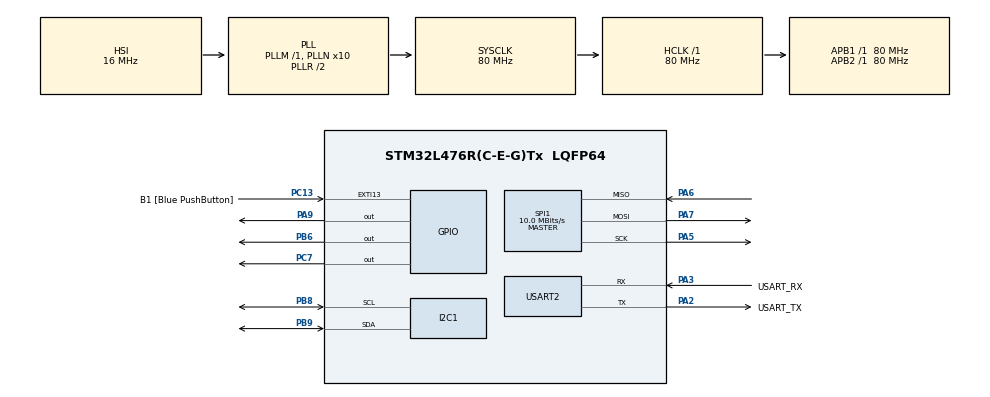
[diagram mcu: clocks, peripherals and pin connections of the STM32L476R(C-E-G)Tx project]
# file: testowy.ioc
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I2C1.Timing=0x10909CEC
Mcu.Family=STM32L4
Mcu.Name=STM32L476R(C-E-G)Tx
Mcu.Package=LQFP64
NVIC.PriorityGroup=NVIC_PRIORITYGROUP_4
PA13\ (JTMS-SWDIO).GPIO_Label=TMS
PA13\ (JTMS-SWDIO).Mode=Serial_Wire
PA13\ (JTMS-SWDIO).Signal=SYS_JTMS-SWDIO
PA14\ (JTCK-SWCLK).GPIO_Label=TCK
PA14\ (JTCK-SWCLK).Mode=Serial_Wire
PA14\ (JTCK-SWCLK).Signal=SYS_JTCK-SWCLK
PA2.GPIO_Label=USART_TX
PA2.GPIO_Mode=GPIO_MODE_AF_PP
PA2.GPIO_PuPd=GPIO_NOPULL
PA2.GPIO_Speed=GPIO_SPEED_FREQ_VERY_HIGH
PA2.Mode=Asynchronous
PA2.Signal=USART2_TX
PA3.GPIO_Label=USART_RX
PA3.GPIO_Mode=GPIO_MODE_AF_PP
PA3.GPIO_PuPd=GPIO_NOPULL
PA3.GPIO_Speed=GPIO_SPEED_FREQ_VERY_HIGH
PA3.Mode=Asynchronous
PA3.Signal=USART2_RX
PA5.Mode=Full_Duplex_Master
PA5.Signal=SPI1_SCK
PA6.Mode=Full_Duplex_Master
PA6.Signal=SPI1_MISO
PA7.Mode=Full_Duplex_Master
PA7.Signal=SPI1_MOSI
PA9.Signal=GPIO_Output
PB3\ (JTDO-TRACESWO).GPIO_Label=SWO
PB3\ (JTDO-TRACESWO).Signal=SYS_JTDO-SWO
PB6.Signal=GPIO_Output
PB8.Mode=I2C
PB8.Signal=I2C1_SCL
PB9.Mode=I2C
PB9.Signal=I2C1_SDA
PC13.GPIO_Label=B1 [Blue PushButton]
PC13.GPIO_ModeDefaultEXTI=GPIO_MODE_IT_FALLING
PC13.GPIO_PuPd=GPIO_NOPULL
PC13.Signal=GPXTI13
PC14-OSC32_IN\ (PC14).Mode=LSE-External-Oscillator
PC14-OSC32_IN\ (PC14).Signal=RCC_OSC32_IN
PC15-OSC32_OUT\ (PC15).Mode=LSE-External-Oscillator
PC15-OSC32_OUT\ (PC15).Signal=RCC_OSC32_OUT
PC7.Signal=GPIO_Output
PH0-OSC_IN\ (PH0).Signal=RCC_OSC_IN
PH1-OSC_OUT\ (PH1).Signal=RCC_OSC_OUT
ProjectManager.HeapSize=0x200
ProjectManager.StackSize=0x400
ProjectManager.TargetToolchain=STM32CubeIDE
RCC.ADCFreq_Value=64000000
RCC.AHBFreq_Value=80000000
RCC.APB1Freq_Value=80000000
RCC.APB1TimFreq_Value=80000000
RCC.APB2Freq_Value=80000000
RCC.APB2TimFreq_Value=80000000
RCC.CortexFreq_Value=80000000
RCC.HCLKFreq_Value=80000000
RCC.HSE_VALUE=8000000
RCC.HSI_VALUE=16000000
RCC.MSI_VALUE=4000000
RCC.PLLN=10
RCC.PLLSourceVirtual=RCC_PLLSOURCE_HSI
RCC.PREFETCH_ENABLE=1
RCC.SYSCLKFreq_VALUE=80000000
RCC.SYSCLKSource=RCC_SYSCLKSOURCE_PLLCLK
RCC.USBFreq_Value=64000000
RCC.VCOOutputFreq_Value=160000000
SPI1.BaudRatePrescaler=SPI_BAUDRATEPRESCALER_8
SPI1.CalculateBaudRate=10.0 MBits/s
SPI1.DataSize=SPI_DATASIZE_8BIT
SPI1.Direction=SPI_DIRECTION_2LINES
SPI1.Mode=SPI_MODE_MASTER
SPI1.VirtualType=VM_MASTER
USART2.VirtualMode-Asynchronous=VM_ASYNC
board=NUCLEO-L476RG

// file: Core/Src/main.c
/* USER CODE BEGIN Header */
/**
  ******************************************************************************
  * @file           : main.c
  * @brief          : Main program body
  ******************************************************************************
  * @attention
  *
  * Copyright (c) 2024 STMicroelectronics.
  * All rights reserved.
  *
  * This software is licensed under terms that can be found in the LICENSE file
  * in the root directory of this software component.
  * If no LICENSE file comes with this software, it is provided AS-IS.
  *
  ******************************************************************************
  */
/* USER CODE END Header */
#include "main.h"

#include "ssd1306.h"
#include "ssd1306_tests.h"
#include "sx1509.h"

#include <stdbool.h>

I2C_HandleTypeDef hi2c1;

SPI_HandleTypeDef hspi1;

UART_HandleTypeDef huart2;

void SystemClock_Config(void);
void loop(void);
static void MX_GPIO_Init(void);
static void MX_USART2_UART_Init(void);
static void MX_I2C1_Init(void);
static void MX_SPI1_Init(void);

/* USER CODE BEGIN 0 */

static uint16_t readWordINA(uint8_t reg)
{
	HAL_StatusTypeDef ret;
	uint8_t buf[2] = {reg};
	ret = HAL_I2C_Master_Transmit(&SX1509_I2C_PORT, INAAddress, buf, 1, i2CTimeout);
	if ( ret == HAL_OK )
	{
		ret = HAL_I2C_Master_Receive(&SX1509_I2C_PORT, INAAddress, buf, 2, i2CTimeout);
		if ( ret == HAL_OK )
		{
			uint16_t tmp = buf[0];
			tmp <<= 8;
			tmp |= buf[1];
			return tmp;
		}
	}
	return 0xFFFF;
}

/* USER CODE END 0 */

void loop() {
	// Blue button pressed - repeast the test
    if(HAL_GPIO_ReadPin(GPIOC, GPIO_PIN_13) == GPIO_PIN_RESET) {

		ssd1306_TestAll();

    }

	HAL_Delay(150);
}

int main(void)
{

  /* USER CODE BEGIN 1 */
uint16_t reg=0;
  /* USER CODE END 1 */

  /* MCU Configuration--------------------------------------------------------*/

  /* Reset of all peripherals, Initializes the Flash interface and the Systick. */
  HAL_Init();

  /* Configure the system clock */
  SystemClock_Config();

  /* Initialize all configured peripherals */
  MX_GPIO_Init();
  MX_USART2_UART_Init();
  MX_I2C1_Init();
  MX_SPI1_Init();
  /* USER CODE BEGIN 2 */

	reg = readWord(0x13);

 	reg = readWordINA(0x3F);

  /* USER CODE END 2 */

  /* Infinite loop */
  while (1)
  {

	  loop();
    /* USER CODE BEGIN 3 */

	  reg = readWordINA(0x07);
  }
  /* USER CODE END 3 */
}

void SystemClock_Config(void)
{
  RCC_OscInitTypeDef RCC_OscInitStruct = {0};
  RCC_ClkInitTypeDef RCC_ClkInitStruct = {0};

  /** Configure the main internal regulator output voltage
  */
  if (HAL_PWREx_ControlVoltageScaling(PWR_REGULATOR_VOLTAGE_SCALE1) != HAL_OK)
  {
    Error_Handler();
  }

  /** Initializes the RCC Oscillators according to the specified parameters
  * in the RCC_OscInitTypeDef structure.
  */
  RCC_OscInitStruct.OscillatorType = RCC_OSCILLATORTYPE_HSI;
  RCC_OscInitStruct.HSIState = RCC_HSI_ON;
  RCC_OscInitStruct.HSICalibrationValue = RCC_HSICALIBRATION_DEFAULT;
  RCC_OscInitStruct.PLL.PLLState = RCC_PLL_ON;
  RCC_OscInitStruct.PLL.PLLSource = RCC_PLLSOURCE_HSI;
  RCC_OscInitStruct.PLL.PLLM = 1;
  RCC_OscInitStruct.PLL.PLLN = 10;
  RCC_OscInitStruct.PLL.PLLP = RCC_PLLP_DIV7;
  RCC_OscInitStruct.PLL.PLLQ = RCC_PLLQ_DIV2;
  RCC_OscInitStruct.PLL.PLLR = RCC_PLLR_DIV2;
  if (HAL_RCC_OscConfig(&RCC_OscInitStruct) != HAL_OK)
  {
    Error_Handler();
  }

  /** Initializes the CPU, AHB and APB buses clocks
  */
  RCC_ClkInitStruct.ClockType = RCC_CLOCKTYPE_HCLK|RCC_CLOCKTYPE_SYSCLK
                              |RCC_CLOCKTYPE_PCLK1|RCC_CLOCKTYPE_PCLK2;
  RCC_ClkInitStruct.SYSCLKSource = RCC_SYSCLKSOURCE_PLLCLK;
  RCC_ClkInitStruct.AHBCLKDivider = RCC_SYSCLK_DIV1;
  RCC_ClkInitStruct.APB1CLKDivider = RCC_HCLK_DIV1;
  RCC_ClkInitStruct.APB2CLKDivider = RCC_HCLK_DIV1;

  if (HAL_RCC_ClockConfig(&RCC_ClkInitStruct, FLASH_LATENCY_4) != HAL_OK)
  {
    Error_Handler();
  }
}

static void MX_I2C1_Init(void)
{

  /* USER CODE BEGIN I2C1_Init 0 */
		  GPIO_InitTypeDef GPIO_InitStruct;
		  RCC_PeriphCLKInitTypeDef PeriphClkInit = {0};
		  /** Initializes the peripherals clock  */
		  PeriphClkInit.PeriphClockSelection = RCC_PERIPHCLK_I2C1;
		  PeriphClkInit.Usart2ClockSelection = RCC_I2C1CLKSOURCE_PCLK1;
		  HAL_RCCEx_PeriphCLKConfig(&PeriphClkInit);

		  /* Enable Peripheral clock */
		  __HAL_RCC_I2C1_CLK_ENABLE();

		    __HAL_RCC_GPIOB_CLK_ENABLE();
		    /**USART2 GPIO Configuration
		    PA2     ------> USART2_TX
		    PA3     ------> USART2_RX
		    */
		    GPIO_InitStruct.Pin = GPIO_PIN_8 | GPIO_PIN_9;
		    GPIO_InitStruct.Mode = GPIO_MODE_AF_PP;
		    GPIO_InitStruct.Pull = GPIO_PULLUP;
		    GPIO_InitStruct.Speed = GPIO_SPEED_FREQ_VERY_HIGH;
		    GPIO_InitStruct.Alternate = GPIO_AF4_I2C1;
		    HAL_GPIO_Init(GPIOB, &GPIO_InitStruct);

  /* USER CODE END I2C1_Init 0 */

  hi2c1.Instance = I2C1;
  hi2c1.Init.Timing = 0x10909CEC;
  hi2c1.Init.OwnAddress1 = 0;
  hi2c1.Init.AddressingMode = I2C_ADDRESSINGMODE_7BIT;
  hi2c1.Init.DualAddressMode = I2C_DUALADDRESS_DISABLE;
  hi2c1.Init.OwnAddress2 = 0;
  hi2c1.Init.OwnAddress2Masks = I2C_OA2_NOMASK;
  hi2c1.Init.GeneralCallMode = I2C_GENERALCALL_DISABLE;
  hi2c1.Init.NoStretchMode = I2C_NOSTRETCH_DISABLE;
  if (HAL_I2C_Init(&hi2c1) != HAL_OK)
  {
    Error_Handler();
  }

  /** Configure Analogue filter
  */
  if (HAL_I2CEx_ConfigAnalogFilter(&hi2c1, I2C_ANALOGFILTER_ENABLE) != HAL_OK)
  {
    Error_Handler();
  }

  /** Configure Digital filter
  */
  if (HAL_I2CEx_ConfigDigitalFilter(&hi2c1, 0) != HAL_OK)
  {
    Error_Handler();
  }

}

static void MX_SPI1_Init(void)
{

  /* SPI1 parameter configuration*/
  hspi1.Instance = SPI1;
  hspi1.Init.Mode = SPI_MODE_MASTER;
  hspi1.Init.Direction = SPI_DIRECTION_2LINES;
  hspi1.Init.DataSize = SPI_DATASIZE_8BIT;
  hspi1.Init.CLKPolarity = SPI_POLARITY_LOW;
  hspi1.Init.CLKPhase = SPI_PHASE_1EDGE;
  hspi1.Init.NSS = SPI_NSS_SOFT;
  hspi1.Init.BaudRatePrescaler = SPI_BAUDRATEPRESCALER_8;
  hspi1.Init.FirstBit = SPI_FIRSTBIT_MSB;
  hspi1.Init.TIMode = SPI_TIMODE_DISABLE;
  hspi1.Init.CRCCalculation = SPI_CRCCALCULATION_DISABLE;
  hspi1.Init.CRCPolynomial = 7;
  hspi1.Init.CRCLength = SPI_CRC_LENGTH_DATASIZE;
  hspi1.Init.NSSPMode = SPI_NSS_PULSE_ENABLE;
  if (HAL_SPI_Init(&hspi1) != HAL_OK)
  {
    Error_Handler();
  }

}

static void MX_USART2_UART_Init(void)
{

  huart2.Instance = USART2;
  huart2.Init.BaudRate = 115200;
  huart2.Init.WordLength = UART_WORDLENGTH_8B;
  huart2.Init.StopBits = UART_STOPBITS_1;
  huart2.Init.Parity = UART_PARITY_NONE;
  huart2.Init.Mode = UART_MODE_TX_RX;
  huart2.Init.HwFlowCtl = UART_HWCONTROL_NONE;
  huart2.Init.OverSampling = UART_OVERSAMPLING_16;
  huart2.Init.OneBitSampling = UART_ONE_BIT_SAMPLE_DISABLE;
  huart2.AdvancedInit.AdvFeatureInit = UART_ADVFEATURE_NO_INIT;
  if (HAL_UART_Init(&huart2) != HAL_OK)
  {
    Error_Handler();
  }

}

static void MX_GPIO_Init(void)
{
  GPIO_InitTypeDef GPIO_InitStruct = {0};

  /* GPIO Ports Clock Enable */
  __HAL_RCC_GPIOC_CLK_ENABLE();
  __HAL_RCC_GPIOH_CLK_ENABLE();
  __HAL_RCC_GPIOA_CLK_ENABLE();
  __HAL_RCC_GPIOB_CLK_ENABLE();

  /*Configure GPIO pin Output Level */
  HAL_GPIO_WritePin(GPIOC, GPIO_PIN_7, GPIO_PIN_RESET);

  /*Configure GPIO pin Output Level */
  HAL_GPIO_WritePin(GPIOA, GPIO_PIN_9, GPIO_PIN_RESET);

  /*Configure GPIO pin Output Level */
  HAL_GPIO_WritePin(GPIOB, GPIO_PIN_6, GPIO_PIN_RESET);

  /*Configure GPIO pin Output Level */
  HAL_GPIO_WritePin(SSD1306_CS_Port,SSD1306_CS_Pin , GPIO_PIN_RESET);
  HAL_GPIO_WritePin(SSD1306_DC_Port,SSD1306_DC_Pin , GPIO_PIN_RESET);
  HAL_GPIO_WritePin(SSD1306_Reset_Port, SSD1306_Reset_Pin, GPIO_PIN_RESET);

  /*Configure GPIO pin : B1_Pin */
  GPIO_InitStruct.Pin = B1_Pin;
  GPIO_InitStruct.Mode = GPIO_MODE_IT_FALLING;
  GPIO_InitStruct.Pull = GPIO_NOPULL;
  HAL_GPIO_Init(B1_GPIO_Port, &GPIO_InitStruct);

  GPIO_InitStruct.Pin = GPIO_PIN_5 | GPIO_PIN_7;
  GPIO_InitStruct.Mode = GPIO_MODE_AF_PP;
  GPIO_InitStruct.Pull = GPIO_NOPULL;
  GPIO_InitStruct.Speed = GPIO_SPEED_FREQ_VERY_HIGH;
  GPIO_InitStruct.Alternate = GPIO_AF5_SPI1;
  HAL_GPIO_Init(GPIOA, &GPIO_InitStruct);

  /*Configure GPIO pins : OLED_CS_Pin OLED_DC_Pin */
  GPIO_InitStruct.Pin = SSD1306_CS_Pin;
  GPIO_InitStruct.Mode = GPIO_MODE_OUTPUT_PP;
  GPIO_InitStruct.Pull = GPIO_NOPULL;
  GPIO_InitStruct.Speed = GPIO_SPEED_FREQ_LOW;
  HAL_GPIO_Init(SSD1306_CS_Port, &GPIO_InitStruct);

  GPIO_InitStruct.Pin = SSD1306_DC_Pin;
  GPIO_InitStruct.Mode = GPIO_MODE_OUTPUT_PP;
  GPIO_InitStruct.Pull = GPIO_NOPULL;
  GPIO_InitStruct.Speed = GPIO_SPEED_FREQ_LOW;
  HAL_GPIO_Init(SSD1306_DC_Port, &GPIO_InitStruct);

  GPIO_InitStruct.Pin =  SX1509_OSC_Pin | SX1509_nRST_Pin;
  GPIO_InitStruct.Mode = GPIO_MODE_OUTPUT_PP;
  GPIO_InitStruct.Pull = GPIO_NOPULL;
  GPIO_InitStruct.Speed = GPIO_SPEED_FREQ_LOW;
  HAL_GPIO_Init(SX1509_nINIT_PORT, &GPIO_InitStruct);

  GPIO_InitStruct.Pin = SX1509_nINIT_Pin ;
    GPIO_InitStruct.Mode = GPIO_MODE_INPUT;
    GPIO_InitStruct.Pull = GPIO_NOPULL;
    GPIO_InitStruct.Speed = GPIO_SPEED_FREQ_LOW;
    HAL_GPIO_Init(SX1509_nINIT_PORT, &GPIO_InitStruct);

  /*Configure GPIO pins : USART_TX_Pin USART_RX_Pin */
  GPIO_InitStruct.Pin = USART_TX_Pin|USART_RX_Pin;
  GPIO_InitStruct.Mode = GPIO_MODE_AF_PP;
  GPIO_InitStruct.Pull = GPIO_NOPULL;
  GPIO_InitStruct.Speed = GPIO_SPEED_FREQ_VERY_HIGH;
  GPIO_InitStruct.Alternate = GPIO_AF7_USART2;
  HAL_GPIO_Init(GPIOA, &GPIO_InitStruct);

  /*Configure GPIO pin : OLED_Res_Pin */
  GPIO_InitStruct.Pin = SSD1306_Reset_Pin;
  GPIO_InitStruct.Mode = GPIO_MODE_OUTPUT_PP;
  GPIO_InitStruct.Pull = GPIO_NOPULL;
  GPIO_InitStruct.Speed = GPIO_SPEED_FREQ_LOW;
  HAL_GPIO_Init(SSD1306_Reset_Port, &GPIO_InitStruct);

  HAL_GPIO_WritePin(SX1509_nRST_PORT, SX1509_nRST_Pin, GPIO_PIN_SET);

}

void Error_Handler(void)
{
  __disable_irq();
  while (1)
  {
  }
}
